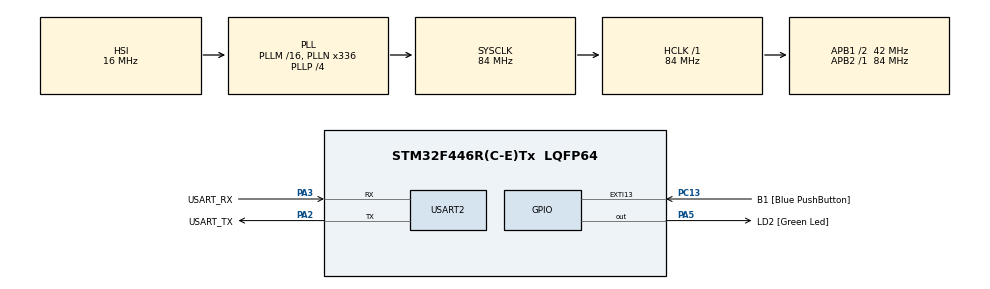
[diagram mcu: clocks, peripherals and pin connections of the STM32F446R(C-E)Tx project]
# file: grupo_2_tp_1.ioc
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FREERTOS.Tasks01=defaultTask,0,128,StartDefaultTask,Default,NULL,Dynamic,NULL,NULL
FREERTOS.configUSE_NEWLIB_REENTRANT=1
Mcu.Family=STM32F4
Mcu.Name=STM32F446R(C-E)Tx
Mcu.Package=LQFP64
NVIC.PriorityGroup=NVIC_PRIORITYGROUP_4
NVIC.TIM1_UP_TIM10_IRQn=true\:15\:0\:false\:false\:true\:false\:false\:true\:true
NVIC.TimeBase=TIM1_UP_TIM10_IRQn
NVIC.TimeBaseIP=TIM1
PA13.GPIO_Label=TMS
PA13.Mode=Serial_Wire
PA13.Signal=SYS_JTMS-SWDIO
PA14.GPIO_Label=TCK
PA14.Mode=Serial_Wire
PA14.Signal=SYS_JTCK-SWCLK
PA2.GPIO_Label=USART_TX
PA2.Mode=Asynchronous
PA2.Signal=USART2_TX
PA3.GPIO_Label=USART_RX
PA3.Mode=Asynchronous
PA3.Signal=USART2_RX
PA5.GPIO_Label=LD2 [Green Led]
PA5.Signal=GPIO_Output
PB3.GPIO_Label=SWO
PB3.Signal=SYS_JTDO-SWO
PC13.GPIO_Label=B1 [Blue PushButton]
PC13.GPIO_ModeDefaultEXTI=GPIO_MODE_IT_FALLING
PC13.Signal=GPXTI13
PC14-OSC32_IN.Mode=LSE-External-Oscillator
PC14-OSC32_IN.Signal=RCC_OSC32_IN
PC15-OSC32_OUT.Mode=LSE-External-Oscillator
PC15-OSC32_OUT.Signal=RCC_OSC32_OUT
PH0-OSC_IN.Mode=HSE-External-Oscillator
PH0-OSC_IN.Signal=RCC_OSC_IN
PH1-OSC_OUT.Mode=HSE-External-Oscillator
PH1-OSC_OUT.Signal=RCC_OSC_OUT
ProjectManager.HeapSize=0x200
ProjectManager.StackSize=0x400
ProjectManager.TargetToolchain=STM32CubeIDE
RCC.48MHZClocksFreq_Value=84000000
RCC.AHBFreq_Value=84000000
RCC.APB1CLKDivider=RCC_HCLK_DIV2
RCC.APB1Freq_Value=42000000
RCC.APB1TimFreq_Value=84000000
RCC.APB2Freq_Value=84000000
RCC.APB2TimFreq_Value=84000000
RCC.CortexFreq_Value=84000000
RCC.FLatency-AdvancedSettings=FLASH_LATENCY_2
RCC.HCLKFreq_Value=84000000
RCC.HSE_VALUE=8000000
RCC.HSI_VALUE=16000000
RCC.PLLN=336
RCC.PLLP=RCC_PLLP_DIV4
RCC.SYSCLKFreq_VALUE=84000000
RCC.SYSCLKSource=RCC_SYSCLKSOURCE_PLLCLK
RCC.USBFreq_Value=168000000
RCC.VCOOutputFreq_Value=336000000
USART2.VirtualMode=VM_ASYNC
VP_FREERTOS_VS_CMSIS_V1.Mode=CMSIS_V1
VP_SYS_VS_tim1.Mode=TIM1
board=NUCLEO-F446RE

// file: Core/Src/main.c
/* USER CODE BEGIN Header */
/**
  ******************************************************************************
  * @file           : main.c
  * @brief          : Main program body
  ******************************************************************************
  * @attention
  *
  * Copyright (c) 2025 STMicroelectronics.
  * All rights reserved.
  *
  * This software is licensed under terms that can be found in the LICENSE file
  * in the root directory of this software component.
  * If no LICENSE file comes with this software, it is provided AS-IS.
  *
  ******************************************************************************
  */
/* USER CODE END Header */
#include "main.h"
#include "cmsis_os.h"

/* USER CODE BEGIN Includes */
/* Demo includes. */
#include "logger.h"
#include "dwt.h"

/* Application includes. */
#include "app.h"

/* USER CODE END Includes */

UART_HandleTypeDef huart2;

osThreadId defaultTaskHandle;

void SystemClock_Config(void);
static void MX_GPIO_Init(void);
static void MX_USART2_UART_Init(void);
void StartDefaultTask(void const * argument);

/* USER CODE BEGIN 0 */
extern void initialise_monitor_handles(void);
/* USER CODE END 0 */

int main(void)
{

  /* USER CODE BEGIN 1 */
  initialise_monitor_handles();
  /* USER CODE END 1 */

  /* MCU Configuration--------------------------------------------------------*/

  /* Reset of all peripherals, Initializes the Flash interface and the Systick. */
  HAL_Init();

  /* Configure the system clock */
  SystemClock_Config();

  /* Initialize all configured peripherals */
  MX_GPIO_Init();
  MX_USART2_UART_Init();

  /* Create the thread(s) */
  /* definition and creation of defaultTask */
  osThreadDef(defaultTask, StartDefaultTask, osPriorityNormal, 0, 128);
  defaultTaskHandle = osThreadCreate(osThread(defaultTask), NULL);

  /* USER CODE BEGIN RTOS_THREADS */
  /* add threads, ... */
  app_init();
  /* USER CODE END RTOS_THREADS */

  /* Start scheduler */
  osKernelStart();

  /* We should never get here as control is now taken by the scheduler */

  /* Infinite loop */
  while (1)
  {

  }
}

void SystemClock_Config(void)
{
  RCC_OscInitTypeDef RCC_OscInitStruct = {0};
  RCC_ClkInitTypeDef RCC_ClkInitStruct = {0};

  /** Configure the main internal regulator output voltage
  */
  __HAL_RCC_PWR_CLK_ENABLE();
  __HAL_PWR_VOLTAGESCALING_CONFIG(PWR_REGULATOR_VOLTAGE_SCALE3);

  /** Initializes the RCC Oscillators according to the specified parameters
  * in the RCC_OscInitTypeDef structure.
  */
  RCC_OscInitStruct.OscillatorType = RCC_OSCILLATORTYPE_HSI;
  RCC_OscInitStruct.HSIState = RCC_HSI_ON;
  RCC_OscInitStruct.HSICalibrationValue = RCC_HSICALIBRATION_DEFAULT;
  RCC_OscInitStruct.PLL.PLLState = RCC_PLL_ON;
  RCC_OscInitStruct.PLL.PLLSource = RCC_PLLSOURCE_HSI;
  RCC_OscInitStruct.PLL.PLLM = 16;
  RCC_OscInitStruct.PLL.PLLN = 336;
  RCC_OscInitStruct.PLL.PLLP = RCC_PLLP_DIV4;
  RCC_OscInitStruct.PLL.PLLQ = 2;
  RCC_OscInitStruct.PLL.PLLR = 2;
  if (HAL_RCC_OscConfig(&RCC_OscInitStruct) != HAL_OK)
  {
    Error_Handler();
  }

  /** Initializes the CPU, AHB and APB buses clocks
  */
  RCC_ClkInitStruct.ClockType = RCC_CLOCKTYPE_HCLK|RCC_CLOCKTYPE_SYSCLK
                              |RCC_CLOCKTYPE_PCLK1|RCC_CLOCKTYPE_PCLK2;
  RCC_ClkInitStruct.SYSCLKSource = RCC_SYSCLKSOURCE_PLLCLK;
  RCC_ClkInitStruct.AHBCLKDivider = RCC_SYSCLK_DIV1;
  RCC_ClkInitStruct.APB1CLKDivider = RCC_HCLK_DIV2;
  RCC_ClkInitStruct.APB2CLKDivider = RCC_HCLK_DIV1;

  if (HAL_RCC_ClockConfig(&RCC_ClkInitStruct, FLASH_LATENCY_2) != HAL_OK)
  {
    Error_Handler();
  }
}

static void MX_USART2_UART_Init(void)
{

  huart2.Instance = USART2;
  huart2.Init.BaudRate = 115200;
  huart2.Init.WordLength = UART_WORDLENGTH_8B;
  huart2.Init.StopBits = UART_STOPBITS_1;
  huart2.Init.Parity = UART_PARITY_NONE;
  huart2.Init.Mode = UART_MODE_TX_RX;
  huart2.Init.HwFlowCtl = UART_HWCONTROL_NONE;
  huart2.Init.OverSampling = UART_OVERSAMPLING_16;
  if (HAL_UART_Init(&huart2) != HAL_OK)
  {
    Error_Handler();
  }

}

static void MX_GPIO_Init(void)
{
  GPIO_InitTypeDef GPIO_InitStruct = {0};

  /* GPIO Ports Clock Enable */
  __HAL_RCC_GPIOC_CLK_ENABLE();
  __HAL_RCC_GPIOH_CLK_ENABLE();
  __HAL_RCC_GPIOA_CLK_ENABLE();
  __HAL_RCC_GPIOB_CLK_ENABLE();

  /*Configure GPIO pin Output Level */
  HAL_GPIO_WritePin(LD2_GPIO_Port, LD2_Pin, GPIO_PIN_RESET);

  /*Configure GPIO pin : B1_Pin */
  GPIO_InitStruct.Pin = B1_Pin;
  GPIO_InitStruct.Mode = GPIO_MODE_IT_FALLING;
  GPIO_InitStruct.Pull = GPIO_NOPULL;
  HAL_GPIO_Init(B1_GPIO_Port, &GPIO_InitStruct);

  /*Configure GPIO pin : LD2_Pin */
  GPIO_InitStruct.Pin = LD2_Pin;
  GPIO_InitStruct.Mode = GPIO_MODE_OUTPUT_PP;
  GPIO_InitStruct.Pull = GPIO_NOPULL;
  GPIO_InitStruct.Speed = GPIO_SPEED_FREQ_LOW;
  HAL_GPIO_Init(LD2_GPIO_Port, &GPIO_InitStruct);

# ifndef BOTONERA
  /*Configure GPIO pins : LD1_Pin LD3_Pin */
  GPIO_InitStruct.Pin = LD1_Pin|LD3_Pin;
  GPIO_InitStruct.Mode = GPIO_MODE_OUTPUT_PP;
  GPIO_InitStruct.Pull = GPIO_NOPULL;
  GPIO_InitStruct.Speed = GPIO_SPEED_FREQ_LOW;
  HAL_GPIO_Init(GPIOA, &GPIO_InitStruct);

  /*Configure GPIO pin : BT1_Pin */
  GPIO_InitStruct.Pin = BT1_Pin;
  GPIO_InitStruct.Mode = GPIO_MODE_INPUT;
  GPIO_InitStruct.Pull = GPIO_NOPULL;
  HAL_GPIO_Init(BT1_GPIO_Port, &GPIO_InitStruct);

  /*Configure GPIO pin : BT2_Pin */
  GPIO_InitStruct.Pin = BT2_Pin;
  GPIO_InitStruct.Mode = GPIO_MODE_INPUT;
  GPIO_InitStruct.Pull = GPIO_NOPULL;
  HAL_GPIO_Init(BT2_GPIO_Port, &GPIO_InitStruct);

  /*Configure GPIO pin : BT3_Pin */
  GPIO_InitStruct.Pin = BT3_Pin;
  GPIO_InitStruct.Mode = GPIO_MODE_INPUT;
  GPIO_InitStruct.Pull = GPIO_NOPULL;
  HAL_GPIO_Init(BT3_GPIO_Port, &GPIO_InitStruct);
#endif
}

void StartDefaultTask(void const * argument)
{
  for(;;)
  {
    osDelay(1);
  }
}

void HAL_TIM_PeriodElapsedCallback(TIM_HandleTypeDef *htim)
{
  if (htim->Instance == TIM1)
  {
    HAL_IncTick();
  }
}

void Error_Handler(void)
{
  __disable_irq();
  while (1)
  {
  }
}
